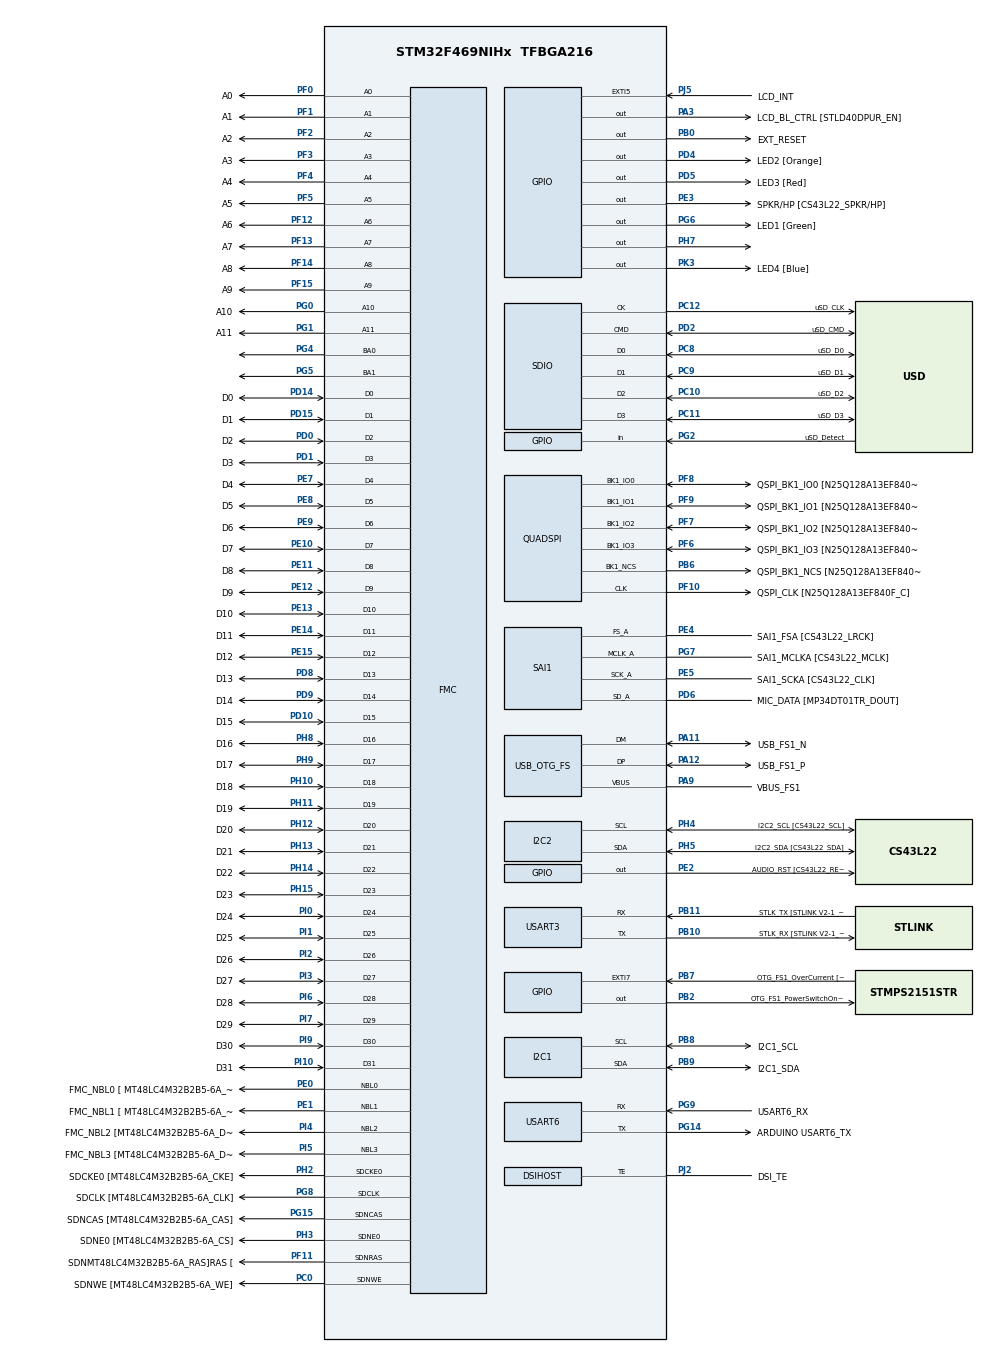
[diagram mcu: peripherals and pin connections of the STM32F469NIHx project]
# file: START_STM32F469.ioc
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DMA2D.ColorMode=DMA2D_OUTPUT_RGB565
DSIHOST.LPDcsLongWrite=DSI_LP_DLW_ENABLE
DSIHOST.LPDcsShortReadNoP=DSI_LP_DSR0P_ENABLE
DSIHOST.LPDcsShortWriteNoP=DSI_LP_DSW0P_ENABLE
DSIHOST.LPDcsShortWriteOneP=DSI_LP_DSW1P_ENABLE
DSIHOST.LPGenLongWrite=DSI_LP_GLW_ENABLE
DSIHOST.LPGenShortReadNoP=DSI_LP_GSR0P_ENABLE
DSIHOST.LPGenShortReadOneP=DSI_LP_GSR1P_ENABLE
DSIHOST.LPGenShortReadTwoP=DSI_LP_GSR2P_ENABLE
DSIHOST.LPGenShortWriteNoP=DSI_LP_GSW0P_ENABLE
DSIHOST.LPGenShortWriteOneP=DSI_LP_GSW1P_ENABLE
DSIHOST.LPGenShortWriteTwoP=DSI_LP_GSW2P_ENABLE
DSIHOST.LPMaxReadPacket=DSI_LP_MRDP_ENABLE
DSIHOST.NumberOfLanes=DSI_TWO_DATA_LANES
DSIHOST.StopWaitTime=10
DSIHOST.TEAcknowledgeRequest=DSI_TE_ACKNOWLEDGE_ENABLE
DSIHOST_CKN.GPIO_Label=DSI_CK_N
DSIHOST_CKN.Mode=DSIHost_Adapted_TE
DSIHOST_CKN.Signal=DSIHOST_CKN
DSIHOST_CKP.GPIO_Label=DSI_CK_P
DSIHOST_CKP.Mode=DSIHost_Adapted_TE
DSIHOST_CKP.Signal=DSIHOST_CKP
DSIHOST_D0N.GPIO_Label=DSI_D0_N
DSIHOST_D0N.Mode=DSIHost_Adapted_TE
DSIHOST_D0N.Signal=DSIHOST_D0N
DSIHOST_D0P.GPIO_Label=DSI_D0_P
DSIHOST_D0P.Mode=DSIHost_Adapted_TE
DSIHOST_D0P.Signal=DSIHOST_D0P
DSIHOST_D1N.GPIO_Label=DSI_D1_N
DSIHOST_D1N.Mode=DSIHost_Adapted_TE
DSIHOST_D1N.Signal=DSIHOST_D1N
DSIHOST_D1P.GPIO_Label=DSI_D1_P
DSIHOST_D1P.Mode=DSIHost_Adapted_TE
DSIHOST_D1P.Signal=DSIHOST_D1P
FATFS.BSP.number=1
FATFS0.BSP.STBoard=false
FATFS0.BSP.api=UnknownBspDriver
FATFS0.BSP.i2caddr=0
FATFS0.BSP.i2creg=0
FATFS0.BSP.instance=PG2
FATFS0.BSP.ip=GPIO
FATFS0.BSP.mode=Input
FATFS0.BSP.name=Detect_SDIO
FATFS0.BSP.solution=PG2
FMC.CASLatency1=FMC_SDRAM_CAS_LATENCY_1
FMC.ExitSelfRefreshDelay1=7
FMC.LoadToActiveDelay1=2
FMC.RCDDelay1=1
FMC.RPDelay1=1
FMC.RPDelay2=2
FMC.ReadBurst1=FMC_SDRAM_RBURST_ENABLE
FMC.ReadBurst2=FMC_SDRAM_RBURST_ENABLE
FMC.RowCycleDelay1=7
FMC.RowCycleDelay2=7
FMC.SDClockPeriod1=FMC_SDRAM_CLOCK_PERIOD_2
FMC.SDClockPeriod2=FMC_SDRAM_CLOCK_PERIOD_2
FMC.SelfRefreshTime1=4
FMC.WriteRecoveryTime1=3
LTDC.Alpha_L0=255
LTDC.BlendingFactor1_L0=LTDC_BLENDING_FACTOR1_PAxCA
LTDC.BlendingFactor2_L0=LTDC_BLENDING_FACTOR2_PAxCA
LTDC.FBStartAdress_L0=0xC0000000
LTDC.HBP=1
LTDC.HFP=1
LTDC.HSync=1
LTDC.ImageHeight_L0=480
LTDC.ImageWidth_L0=200
LTDC.Layers=0
LTDC.PixelFormat_L0=LTDC_PIXEL_FORMAT_RGB565
LTDC.VBP=1
LTDC.VFP=1
LTDC.VSync=1
LTDC.WindowX1_L0=200
LTDC.WindowY1_L0=480
Mcu.Family=STM32F4
Mcu.Name=STM32F469NIHx
Mcu.Package=TFBGA216
NVIC.DMA2D_IRQn=true\:0\:0\:false\:false\:true\:true\:true
NVIC.DSI_IRQn=true\:0\:0\:false\:false\:true\:true\:true
NVIC.LTDC_IRQn=true\:0\:0\:false\:false\:true\:true\:true
NVIC.OTG_FS_IRQn=true\:0\:0\:false\:false\:true\:true\:true
NVIC.PriorityGroup=NVIC_PRIORITYGROUP_4
NVIC.TIM6_DAC_IRQn=true\:0\:0\:false\:false\:true\:false\:true
NVIC.TimeBase=TIM6_DAC_IRQn
NVIC.TimeBaseIP=TIM6
PA0/WKUP.GPIO_Label=WAKEUP [B2]
PA0/WKUP.Mode=SYS_WakeUp0
PA0/WKUP.Signal=SYS_WKUP
PA10.GPIO_Label=USB_FS1_ID
PA10.GPIO_Mode=GPIO_MODE_AF_PP
PA10.GPIO_PuPd=GPIO_NOPULL
PA10.GPIO_Speed=GPIO_SPEED_FREQ_VERY_HIGH
PA10.Signal=USB_OTG_FS_ID
PA11.GPIO_Label=USB_FS1_N
PA11.GPIO_Mode=GPIO_MODE_AF_PP
PA11.GPIO_PuPd=GPIO_NOPULL
PA11.GPIO_Speed=GPIO_SPEED_FREQ_VERY_HIGH
PA11.Mode=Device_Only
PA11.Signal=USB_OTG_FS_DM
PA12.GPIO_Label=USB_FS1_P
PA12.GPIO_Mode=GPIO_MODE_AF_PP
PA12.GPIO_PuPd=GPIO_NOPULL
PA12.GPIO_Speed=GPIO_SPEED_FREQ_VERY_HIGH
PA12.Mode=Device_Only
PA12.Signal=USB_OTG_FS_DP
PA13.GPIO_Label=SWDIO
PA13.Mode=Serial_Wire
PA13.Signal=SYS_JTMS-SWDIO
PA14.GPIO_Label=SWCLK
PA14.Mode=Serial_Wire
PA14.Signal=SYS_JTCK-SWCLK
PA3.GPIO_Label=LCD_BL_CTRL [STLD40DPUR_EN]
PA3.GPIO_ModeDefaultOutputPP=GPIO_MODE_OUTPUT_PP
PA3.GPIO_PuPd=GPIO_NOPULL
PA3.GPIO_Speed=GPIO_SPEED_FREQ_LOW
PA3.Signal=GPIO_Output
PA9.GPIO_Label=VBUS_FS1
PA9.GPIO_Mode=GPIO_MODE_AF_PP
PA9.GPIO_PuPd=GPIO_NOPULL
PA9.GPIO_Speed=GPIO_SPEED_FREQ_VERY_HIGH
PA9.Mode=Activate_VBUS
PA9.Signal=USB_OTG_FS_VBUS
PB0.GPIO_Label=EXT_RESET
PB0.GPIO_ModeDefaultOutputPP=GPIO_MODE_OUTPUT_PP
PB0.GPIO_PuPd=GPIO_NOPULL
PB0.GPIO_Speed=GPIO_SPEED_FREQ_LOW
PB0.Signal=GPIO_Output
PB10.GPIO_Label=STLK_RX [STLINK V2-1_U2_RX]
PB10.GPIO_Mode=GPIO_MODE_AF_PP
PB10.GPIO_PuPd=GPIO_PULLUP
PB10.GPIO_Speed=GPIO_SPEED_FREQ_VERY_HIGH
PB10.Mode=Asynchronous
PB10.Signal=USART3_TX
PB11.GPIO_Label=STLK_TX [STLINK V2-1_U2_TX]
PB11.GPIO_Mode=GPIO_MODE_AF_PP
PB11.GPIO_PuPd=GPIO_PULLUP
PB11.GPIO_Speed=GPIO_SPEED_FREQ_VERY_HIGH
PB11.Mode=Asynchronous
PB11.Signal=USART3_RX
PB2/BOOT1.GPIO_Label=OTG_FS1_PowerSwitchOn [STMPS2151STR_En]
PB2/BOOT1.GPIO_ModeDefaultOutputPP=GPIO_MODE_OUTPUT_PP
PB2/BOOT1.GPIO_PuPd=GPIO_NOPULL
PB2/BOOT1.GPIO_Speed=GPIO_SPEED_FREQ_LOW
PB2/BOOT1.Signal=GPIO_Output
PB3.GPIO_Label=I2S3_CK
PB3.GPIO_Mode=GPIO_MODE_AF_PP
PB3.GPIO_PuPd=GPIO_NOPULL
PB3.GPIO_Speed=GPIO_SPEED_FREQ_LOW
PB3.Signal=I2S3_CK
PB6.GPIO_Label=QSPI_BK1_NCS [N25Q128A13EF840F_S]
PB6.GPIO_Mode=GPIO_MODE_AF_PP
PB6.GPIO_PuPd=GPIO_NOPULL
PB6.GPIO_Speed=GPIO_SPEED_FREQ_VERY_HIGH
PB6.Mode=Single Bank 1
PB6.Signal=QUADSPI_BK1_NCS
PB7.GPIO_Label=OTG_FS1_OverCurrent [STMPS2151STR_FAULT]
PB7.GPIO_ModeDefaultEXTI=GPIO_MODE_IT_RISING
PB7.GPIO_PuPd=GPIO_NOPULL
PB7.Signal=GPXTI7
PB8.GPIO_Label=I2C1_SCL
PB8.GPIO_Mode=GPIO_MODE_AF_OD
PB8.GPIO_PuPdOD=GPIO_PULLUP
PB8.GPIO_Speed=GPIO_SPEED_FREQ_VERY_HIGH
PB8.Mode=I2C
PB8.Signal=I2C1_SCL
PB9.GPIO_Label=I2C1_SDA
PB9.GPIO_Mode=GPIO_MODE_AF_OD
PB9.GPIO_PuPdOD=GPIO_PULLUP
PB9.GPIO_Speed=GPIO_SPEED_FREQ_VERY_HIGH
PB9.Mode=I2C
PB9.Signal=I2C1_SDA
PC0.GPIO_Label=SDNWE [MT48LC4M32B2B5-6A_WE]
PC0.GPIO_Mode=GPIO_MODE_AF_PP
PC0.GPIO_PuPd=GPIO_NOPULL
PC0.GPIO_Speed_High_Default=GPIO_SPEED_FREQ_VERY_HIGH
PC0.Signal=FMC_SDNWE
PC10.GPIO_Label=uSD_D2
PC10.GPIO_Mode=GPIO_MODE_AF_PP
PC10.GPIO_PuPd=GPIO_NOPULL
PC10.GPIO_Speed_High_Default=GPIO_SPEED_FREQ_VERY_HIGH
PC10.Mode=SD_4_bits_Wide_bus
PC10.Signal=SDIO_D2
PC11.GPIO_Label=uSD_D3
PC11.GPIO_Mode=GPIO_MODE_AF_PP
PC11.GPIO_PuPd=GPIO_NOPULL
PC11.GPIO_Speed_High_Default=GPIO_SPEED_FREQ_VERY_HIGH
PC11.Mode=SD_4_bits_Wide_bus
PC11.Signal=SDIO_D3
PC12.GPIO_Label=uSD_CLK
PC12.GPIO_Mode=GPIO_MODE_AF_PP
PC12.GPIO_PuPd=GPIO_NOPULL
PC12.GPIO_Speed_High_Default=GPIO_SPEED_FREQ_VERY_HIGH
PC12.Mode=SD_4_bits_Wide_bus
PC12.Signal=SDIO_CK
PC14/OSC32_IN.Mode=LSE-External-Oscillator
PC14/OSC32_IN.Signal=RCC_OSC32_IN
PC15/OSC32_OUT.Mode=LSE-External-Oscillator
PC15/OSC32_OUT.Signal=RCC_OSC32_OUT
PC8.GPIO_Label=uSD_D0
PC8.GPIO_Mode=GPIO_MODE_AF_PP
PC8.GPIO_PuPd=GPIO_NOPULL
PC8.GPIO_Speed_High_Default=GPIO_SPEED_FREQ_VERY_HIGH
PC8.Mode=SD_4_bits_Wide_bus
PC8.Signal=SDIO_D0
PC9.GPIO_Label=uSD_D1
PC9.GPIO_Mode=GPIO_MODE_AF_PP
PC9.GPIO_PuPd=GPIO_NOPULL
PC9.GPIO_Speed_High_Default=GPIO_SPEED_FREQ_VERY_HIGH
PC9.Mode=SD_4_bits_Wide_bus
PC9.Signal=SDIO_D1
PD0.GPIO_Label=D2
PD0.GPIO_Mode=GPIO_MODE_AF_PP
PD0.GPIO_PuPd=GPIO_NOPULL
PD0.GPIO_Speed_High_Default=GPIO_SPEED_FREQ_VERY_HIGH
PD0.Signal=FMC_D2_DA2
PD1.GPIO_Label=D3
PD1.GPIO_Mode=GPIO_MODE_AF_PP
PD1.GPIO_PuPd=GPIO_NOPULL
PD1.GPIO_Speed_High_Default=GPIO_SPEED_FREQ_VERY_HIGH
PD1.Signal=FMC_D3_DA3
PD10.GPIO_Label=D15
PD10.GPIO_Mode=GPIO_MODE_AF_PP
PD10.GPIO_PuPd=GPIO_NOPULL
PD10.GPIO_Speed_High_Default=GPIO_SPEED_FREQ_VERY_HIGH
PD10.Signal=FMC_D15_DA15
PD13.GPIO_Label=MIC_CK [MP34DT01TR_CLK]
PD13.GPIO_ModeDefaultPP=GPIO_MODE_AF_PP
PD13.GPIO_PuPd=GPIO_NOPULL
PD13.GPIO_Speed=GPIO_SPEED_FREQ_LOW
PD13.Signal=S_TIM4_CH2
PD14.GPIO_Label=D0
PD14.GPIO_Mode=GPIO_MODE_AF_PP
PD14.GPIO_PuPd=GPIO_NOPULL
PD14.GPIO_Speed_High_Default=GPIO_SPEED_FREQ_VERY_HIGH
PD14.Signal=FMC_D0_DA0
PD15.GPIO_Label=D1
PD15.GPIO_Mode=GPIO_MODE_AF_PP
PD15.GPIO_PuPd=GPIO_NOPULL
PD15.GPIO_Speed_High_Default=GPIO_SPEED_FREQ_VERY_HIGH
PD15.Signal=FMC_D1_DA1
PD2.GPIO_Label=uSD_CMD
PD2.GPIO_Mode=GPIO_MODE_AF_PP
PD2.GPIO_PuPd=GPIO_NOPULL
PD2.GPIO_Speed_High_Default=GPIO_SPEED_FREQ_VERY_HIGH
PD2.Mode=SD_4_bits_Wide_bus
PD2.Signal=SDIO_CMD
PD4.GPIO_Label=LED2 [Orange]
PD4.GPIO_ModeDefaultOutputPP=GPIO_MODE_OUTPUT_OD
PD4.GPIO_PuPd=GPIO_NOPULL
PD4.GPIO_Speed=GPIO_SPEED_FREQ_LOW
PD4.Signal=GPIO_Output
PD5.GPIO_Label=LED3 [Red]
PD5.GPIO_ModeDefaultOutputPP=GPIO_MODE_OUTPUT_OD
PD5.GPIO_PuPd=GPIO_NOPULL
PD5.GPIO_Speed=GPIO_SPEED_FREQ_LOW
PD5.Signal=GPIO_Output
PD6.GPIO_Label=MIC_DATA [MP34DT01TR_DOUT]
PD6.GPIO_Mode=GPIO_MODE_AF_PP
PD6.GPIO_PuPd=GPIO_NOPULL
PD6.GPIO_Speed=GPIO_SPEED_FREQ_LOW
PD6.Mode=SAI_A_MasterWithClock
PD6.Signal=SAI1_SD_A
PD8.GPIO_Label=D13
PD8.GPIO_Mode=GPIO_MODE_AF_PP
PD8.GPIO_PuPd=GPIO_NOPULL
PD8.GPIO_Speed_High_Default=GPIO_SPEED_FREQ_VERY_HIGH
PD8.Signal=FMC_D13_DA13
PD9.GPIO_Label=D14
PD9.GPIO_Mode=GPIO_MODE_AF_PP
PD9.GPIO_PuPd=GPIO_NOPULL
PD9.GPIO_Speed_High_Default=GPIO_SPEED_FREQ_VERY_HIGH
PD9.Signal=FMC_D14_DA14
PE0.GPIO_Label=FMC_NBL0 [ MT48LC4M32B2B5-6A_DQM0]
PE0.GPIO_Mode=GPIO_MODE_AF_PP
PE0.GPIO_PuPd=GPIO_NOPULL
PE0.GPIO_Speed_High_Default=GPIO_SPEED_FREQ_VERY_HIGH
PE0.Signal=FMC_NBL0
PE1.GPIO_Label=FMC_NBL1 [ MT48LC4M32B2B5-6A_DQM1]
PE1.GPIO_Mode=GPIO_MODE_AF_PP
PE1.GPIO_PuPd=GPIO_NOPULL
PE1.GPIO_Speed_High_Default=GPIO_SPEED_FREQ_VERY_HIGH
PE1.Signal=FMC_NBL1
PE10.GPIO_Label=D7
PE10.GPIO_Mode=GPIO_MODE_AF_PP
PE10.GPIO_PuPd=GPIO_NOPULL
PE10.GPIO_Speed_High_Default=GPIO_SPEED_FREQ_VERY_HIGH
PE10.Signal=FMC_D7_DA7
PE11.GPIO_Label=D8
PE11.GPIO_Mode=GPIO_MODE_AF_PP
PE11.GPIO_PuPd=GPIO_NOPULL
PE11.GPIO_Speed_High_Default=GPIO_SPEED_FREQ_VERY_HIGH
PE11.Signal=FMC_D8_DA8
PE12.GPIO_Label=D9
PE12.GPIO_Mode=GPIO_MODE_AF_PP
PE12.GPIO_PuPd=GPIO_NOPULL
PE12.GPIO_Speed_High_Default=GPIO_SPEED_FREQ_VERY_HIGH
PE12.Signal=FMC_D9_DA9
PE13.GPIO_Label=D10
PE13.GPIO_Mode=GPIO_MODE_AF_PP
PE13.GPIO_PuPd=GPIO_NOPULL
PE13.GPIO_Speed_High_Default=GPIO_SPEED_FREQ_VERY_HIGH
PE13.Signal=FMC_D10_DA10
PE14.GPIO_Label=D11
PE14.GPIO_Mode=GPIO_MODE_AF_PP
PE14.GPIO_PuPd=GPIO_NOPULL
PE14.GPIO_Speed_High_Default=GPIO_SPEED_FREQ_VERY_HIGH
PE14.Signal=FMC_D11_DA11
PE15.GPIO_Label=D12
PE15.GPIO_Mode=GPIO_MODE_AF_PP
PE15.GPIO_PuPd=GPIO_NOPULL
PE15.GPIO_Speed_High_Default=GPIO_SPEED_FREQ_VERY_HIGH
PE15.Signal=FMC_D12_DA12
PE2.GPIO_Label=AUDIO_RST [CS43L22_RESET]
PE2.GPIO_ModeDefaultOutputPP=GPIO_MODE_OUTPUT_PP
PE2.GPIO_PuPd=GPIO_NOPULL
PE2.GPIO_Speed=GPIO_SPEED_FREQ_LOW
PE2.Signal=GPIO_Output
PE3.GPIO_Label=SPKR/HP [CS43L22_SPKR/HP]
PE3.GPIO_ModeDefaultOutputPP=GPIO_MODE_OUTPUT_PP
PE3.GPIO_PuPd=GPIO_NOPULL
PE3.GPIO_Speed=GPIO_SPEED_FREQ_LOW
PE3.Signal=GPIO_Output
PE4.GPIO_Label=SAI1_FSA [CS43L22_LRCK]
PE4.GPIO_Mode=GPIO_MODE_AF_PP
PE4.GPIO_PuPd=GPIO_NOPULL
PE4.GPIO_Speed=GPIO_SPEED_FREQ_LOW
PE4.Mode=SAI_A_MasterWithClock
PE4.Signal=SAI1_FS_A
PE5.GPIO_Label=SAI1_SCKA [CS43L22_CLK]
PE5.GPIO_Mode=GPIO_MODE_AF_PP
PE5.GPIO_PuPd=GPIO_NOPULL
PE5.GPIO_Speed=GPIO_SPEED_FREQ_LOW
PE5.Mode=SAI_A_MasterWithClock
PE5.Signal=SAI1_SCK_A
PE7.GPIO_Label=D4
PE7.GPIO_Mode=GPIO_MODE_AF_PP
PE7.GPIO_PuPd=GPIO_NOPULL
PE7.GPIO_Speed_High_Default=GPIO_SPEED_FREQ_VERY_HIGH
PE7.Signal=FMC_D4_DA4
PE8.GPIO_Label=D5
PE8.GPIO_Mode=GPIO_MODE_AF_PP
PE8.GPIO_PuPd=GPIO_NOPULL
PE8.GPIO_Speed_High_Default=GPIO_SPEED_FREQ_VERY_HIGH
PE8.Signal=FMC_D5_DA5
PE9.GPIO_Label=D6
PE9.GPIO_Mode=GPIO_MODE_AF_PP
PE9.GPIO_PuPd=GPIO_NOPULL
PE9.GPIO_Speed_High_Default=GPIO_SPEED_FREQ_VERY_HIGH
PE9.Signal=FMC_D6_DA6
PF0.GPIO_Label=A0
PF0.GPIO_Mode=GPIO_MODE_AF_PP
PF0.GPIO_PuPd=GPIO_NOPULL
PF0.GPIO_Speed_High_Default=GPIO_SPEED_FREQ_VERY_HIGH
PF0.Signal=FMC_A0
PF1.GPIO_Label=A1
PF1.GPIO_Mode=GPIO_MODE_AF_PP
PF1.GPIO_PuPd=GPIO_NOPULL
PF1.GPIO_Speed_High_Default=GPIO_SPEED_FREQ_VERY_HIGH
PF1.Signal=FMC_A1
PF10.GPIO_Label=QSPI_CLK [N25Q128A13EF840F_C]
PF10.GPIO_Mode=GPIO_MODE_AF_PP
PF10.GPIO_PuPd=GPIO_NOPULL
PF10.GPIO_Speed=GPIO_SPEED_FREQ_VERY_HIGH
PF10.Mode=Single Bank 1
PF10.Signal=QUADSPI_CLK
PF11.GPIO_Label=SDNMT48LC4M32B2B5-6A_RAS]RAS [
PF11.GPIO_Mode=GPIO_MODE_AF_PP
PF11.GPIO_PuPd=GPIO_NOPULL
PF11.GPIO_Speed_High_Default=GPIO_SPEED_FREQ_VERY_HIGH
PF11.Signal=FMC_SDNRAS
PF12.GPIO_Label=A6
PF12.GPIO_Mode=GPIO_MODE_AF_PP
PF12.GPIO_PuPd=GPIO_NOPULL
PF12.GPIO_Speed_High_Default=GPIO_SPEED_FREQ_VERY_HIGH
PF12.Signal=FMC_A6
PF13.GPIO_Label=A7
PF13.GPIO_Mode=GPIO_MODE_AF_PP
PF13.GPIO_PuPd=GPIO_NOPULL
PF13.GPIO_Speed_High_Default=GPIO_SPEED_FREQ_VERY_HIGH
PF13.Signal=FMC_A7
PF14.GPIO_Label=A8
PF14.GPIO_Mode=GPIO_MODE_AF_PP
PF14.GPIO_PuPd=GPIO_NOPULL
PF14.GPIO_Speed_High_Default=GPIO_SPEED_FREQ_VERY_HIGH
PF14.Signal=FMC_A8
PF15.GPIO_Label=A9
PF15.GPIO_Mode=GPIO_MODE_AF_PP
PF15.GPIO_PuPd=GPIO_NOPULL
PF15.GPIO_Speed_High_Default=GPIO_SPEED_FREQ_VERY_HIGH
PF15.Signal=FMC_A9
PF2.GPIO_Label=A2
PF2.GPIO_Mode=GPIO_MODE_AF_PP
PF2.GPIO_PuPd=GPIO_NOPULL
PF2.GPIO_Speed_High_Default=GPIO_SPEED_FREQ_VERY_HIGH
PF2.Signal=FMC_A2
PF3.GPIO_Label=A3
PF3.GPIO_Mode=GPIO_MODE_AF_PP
PF3.GPIO_PuPd=GPIO_NOPULL
PF3.GPIO_Speed_High_Default=GPIO_SPEED_FREQ_VERY_HIGH
PF3.Signal=FMC_A3
PF4.GPIO_Label=A4
PF4.GPIO_Mode=GPIO_MODE_AF_PP
PF4.GPIO_PuPd=GPIO_NOPULL
PF4.GPIO_Speed_High_Default=GPIO_SPEED_FREQ_VERY_HIGH
PF4.Signal=FMC_A4
PF5.GPIO_Label=A5
PF5.GPIO_Mode=GPIO_MODE_AF_PP
PF5.GPIO_PuPd=GPIO_NOPULL
PF5.GPIO_Speed_High_Default=GPIO_SPEED_FREQ_VERY_HIGH
PF5.Signal=FMC_A5
PF6.GPIO_Label=QSPI_BK1_IO3 [N25Q128A13EF840F_DQ3]
PF6.GPIO_Mode=GPIO_MODE_AF_PP
PF6.GPIO_PuPd=GPIO_NOPULL
PF6.GPIO_Speed=GPIO_SPEED_FREQ_VERY_HIGH
PF6.Mode=Single Bank 1
PF6.Signal=QUADSPI_BK1_IO3
PF7.GPIO_Label=QSPI_BK1_IO2 [N25Q128A13EF840F_DQ2]
PF7.GPIO_Mode=GPIO_MODE_AF_PP
PF7.GPIO_PuPd=GPIO_NOPULL
PF7.GPIO_Speed=GPIO_SPEED_FREQ_VERY_HIGH
PF7.Mode=Single Bank 1
PF7.Signal=QUADSPI_BK1_IO2
PF8.GPIO_Label=QSPI_BK1_IO0 [N25Q128A13EF840F_DQ0]
PF8.GPIO_Mode=GPIO_MODE_AF_PP
PF8.GPIO_PuPd=GPIO_NOPULL
PF8.GPIO_Speed=GPIO_SPEED_FREQ_VERY_HIGH
PF8.Mode=Single Bank 1
PF8.Signal=QUADSPI_BK1_IO0
PF9.GPIO_Label=QSPI_BK1_IO1 [N25Q128A13EF840F_DQ1]
PF9.GPIO_Mode=GPIO_MODE_AF_PP
PF9.GPIO_PuPd=GPIO_NOPULL
PF9.GPIO_Speed=GPIO_SPEED_FREQ_VERY_HIGH
PF9.Mode=Single Bank 1
PF9.Signal=QUADSPI_BK1_IO1
PG0.GPIO_Label=A10
PG0.GPIO_Mode=GPIO_MODE_AF_PP
PG0.GPIO_PuPd=GPIO_NOPULL
PG0.GPIO_Speed_High_Default=GPIO_SPEED_FREQ_VERY_HIGH
PG0.Signal=FMC_A10
PG1.GPIO_Label=A11
PG1.GPIO_Mode=GPIO_MODE_AF_PP
PG1.GPIO_PuPd=GPIO_NOPULL
PG1.GPIO_Speed_High_Default=GPIO_SPEED_FREQ_VERY_HIGH
PG1.Signal=FMC_A11
PG14.GPIO_Label=ARDUINO USART6_TX
PG14.GPIO_Mode=GPIO_MODE_AF_PP
PG14.GPIO_PuPd=GPIO_NOPULL
PG14.GPIO_Speed=GPIO_SPEED_FREQ_VERY_HIGH
PG14.Mode=Asynchronous
PG14.Signal=USART6_TX
PG15.GPIO_Label=SDNCAS [MT48LC4M32B2B5-6A_CAS]
PG15.GPIO_Mode=GPIO_MODE_AF_PP
PG15.GPIO_PuPd=GPIO_NOPULL
PG15.GPIO_Speed_High_Default=GPIO_SPEED_FREQ_VERY_HIGH
PG15.Signal=FMC_SDNCAS
PG2.GPIO_Label=uSD_Detect
PG2.GPIO_Mode=GPIO_MODE_INPUT
PG2.GPIO_PuPd=GPIO_NOPULL
PG2.Signal=GPIO_Input
PG4.Signal=FMC_A14_BA0
PG5.Signal=FMC_A15_BA1
PG6.GPIO_Label=LED1 [Green]
PG6.GPIO_ModeDefaultOutputPP=GPIO_MODE_OUTPUT_OD
PG6.GPIO_PuPd=GPIO_NOPULL
PG6.GPIO_Speed=GPIO_SPEED_FREQ_LOW
PG6.Signal=GPIO_Output
PG7.GPIO_Label=SAI1_MCLKA [CS43L22_MCLK]
PG7.GPIO_Mode=GPIO_MODE_AF_PP
PG7.GPIO_PuPd=GPIO_NOPULL
PG7.GPIO_Speed=GPIO_SPEED_FREQ_LOW
PG7.Mode=SAI_A_MasterWithClock
PG7.Signal=SAI1_MCLK_A
PG8.GPIO_Label=SDCLK [MT48LC4M32B2B5-6A_CLK]
PG8.GPIO_Mode=GPIO_MODE_AF_PP
PG8.GPIO_PuPd=GPIO_NOPULL
PG8.GPIO_Speed_High_Default=GPIO_SPEED_FREQ_VERY_HIGH
PG8.Signal=FMC_SDCLK
PG9.GPIO_Label=USART6_RX
PG9.GPIO_Mode=GPIO_MODE_AF_PP
PG9.GPIO_PuPd=GPIO_NOPULL
PG9.GPIO_Speed=GPIO_SPEED_FREQ_VERY_HIGH
PG9.Mode=Asynchronous
PG9.Signal=USART6_RX
PH0/OSC_IN.Mode=HSE-External-Oscillator
PH0/OSC_IN.Signal=RCC_OSC_IN
PH1/OSC_OUT.Mode=HSE-External-Oscillator
PH1/OSC_OUT.Signal=RCC_OSC_OUT
PH10.GPIO_Label=D18
PH10.GPIO_Mode=GPIO_MODE_AF_PP
PH10.GPIO_PuPd=GPIO_NOPULL
PH10.GPIO_Speed_High_Default=GPIO_SPEED_FREQ_VERY_HIGH
PH10.Signal=FMC_D18
PH11.GPIO_Label=D19
PH11.GPIO_Mode=GPIO_MODE_AF_PP
PH11.GPIO_PuPd=GPIO_NOPULL
PH11.GPIO_Speed_High_Default=GPIO_SPEED_FREQ_VERY_HIGH
PH11.Signal=FMC_D19
PH12.GPIO_Label=D20
PH12.GPIO_Mode=GPIO_MODE_AF_PP
PH12.GPIO_PuPd=GPIO_NOPULL
PH12.GPIO_Speed_High_Default=GPIO_SPEED_FREQ_VERY_HIGH
PH12.Signal=FMC_D20
PH13.GPIO_Label=D21
PH13.GPIO_Mode=GPIO_MODE_AF_PP
PH13.GPIO_PuPd=GPIO_NOPULL
PH13.GPIO_Speed_High_Default=GPIO_SPEED_FREQ_VERY_HIGH
PH13.Signal=FMC_D21
PH14.GPIO_Label=D22
PH14.GPIO_Mode=GPIO_MODE_AF_PP
PH14.GPIO_PuPd=GPIO_NOPULL
PH14.GPIO_Speed_High_Default=GPIO_SPEED_FREQ_VERY_HIGH
PH14.Signal=FMC_D22
PH15.GPIO_Label=D23
PH15.GPIO_Mode=GPIO_MODE_AF_PP
PH15.GPIO_PuPd=GPIO_NOPULL
PH15.GPIO_Speed_High_Default=GPIO_SPEED_FREQ_VERY_HIGH
PH15.Signal=FMC_D23
PH2.GPIO_Label=SDCKE0 [MT48LC4M32B2B5-6A_CKE]
PH2.GPIO_Mode=GPIO_MODE_AF_PP
PH2.GPIO_PuPd=GPIO_NOPULL
PH2.GPIO_Speed_High_Default=GPIO_SPEED_FREQ_VERY_HIGH
PH2.Mode=SdramChipSelect1_1
PH2.Signal=FMC_SDCKE0
PH3.GPIO_Label=SDNE0 [MT48LC4M32B2B5-6A_CS]
PH3.GPIO_Mode=GPIO_MODE_AF_PP
PH3.GPIO_PuPd=GPIO_NOPULL
PH3.GPIO_Speed_High_Default=GPIO_SPEED_FREQ_VERY_HIGH
PH3.Mode=SdramChipSelect1_1
PH3.Signal=FMC_SDNE0
PH4.GPIO_Label=I2C2_SCL [CS43L22_SCL]
PH4.GPIO_Mode=GPIO_MODE_AF_OD
PH4.GPIO_PuPdOD=GPIO_PULLUP
PH4.GPIO_Speed=GPIO_SPEED_FREQ_VERY_HIGH
PH4.Mode=I2C
PH4.Signal=I2C2_SCL
PH5.GPIO_Label=I2C2_SDA [CS43L22_SDA]
PH5.GPIO_Mode=GPIO_MODE_AF_OD
PH5.GPIO_PuPdOD=GPIO_PULLUP
PH5.GPIO_Speed=GPIO_SPEED_FREQ_VERY_HIGH
PH5.Mode=I2C
PH5.Signal=I2C2_SDA
PH7.Signal=GPIO_Output
PH8.GPIO_Label=D16
PH8.GPIO_Mode=GPIO_MODE_AF_PP
PH8.GPIO_PuPd=GPIO_NOPULL
PH8.GPIO_Speed_High_Default=GPIO_SPEED_FREQ_VERY_HIGH
PH8.Signal=FMC_D16
PH9.GPIO_Label=D17
PH9.GPIO_Mode=GPIO_MODE_AF_PP
PH9.GPIO_PuPd=GPIO_NOPULL
PH9.GPIO_Speed_High_Default=GPIO_SPEED_FREQ_VERY_HIGH
PH9.Signal=FMC_D17
PI0.GPIO_Label=D24
PI0.GPIO_Mode=GPIO_MODE_AF_PP
PI0.GPIO_PuPd=GPIO_NOPULL
PI0.GPIO_Speed_High_Default=GPIO_SPEED_FREQ_VERY_HIGH
PI0.Signal=FMC_D24
PI1.GPIO_Label=D25
PI1.GPIO_Mode=GPIO_MODE_AF_PP
PI1.GPIO_PuPd=GPIO_NOPULL
PI1.GPIO_Speed_High_Default=GPIO_SPEED_FREQ_VERY_HIGH
PI1.Signal=FMC_D25
PI10.GPIO_Label=D31
PI10.GPIO_Mode=GPIO_MODE_AF_PP
PI10.GPIO_PuPd=GPIO_NOPULL
PI10.GPIO_Speed_High_Default=GPIO_SPEED_FREQ_VERY_HIGH
PI10.Signal=FMC_D31
PI2.GPIO_Label=D26
PI2.GPIO_Mode=GPIO_MODE_AF_PP
PI2.GPIO_PuPd=GPIO_NOPULL
PI2.GPIO_Speed_High_Default=GPIO_SPEED_FREQ_VERY_HIGH
PI2.Signal=FMC_D26
PI3.GPIO_Label=D27
PI3.GPIO_Mode=GPIO_MODE_AF_PP
PI3.GPIO_PuPd=GPIO_NOPULL
PI3.GPIO_Speed_High_Default=GPIO_SPEED_FREQ_VERY_HIGH
PI3.Signal=FMC_D27
PI4.GPIO_Label=FMC_NBL2 [MT48LC4M32B2B5-6A_DQM2]
PI4.GPIO_Mode=GPIO_MODE_AF_PP
PI4.GPIO_PuPd=GPIO_NOPULL
PI4.GPIO_Speed_High_Default=GPIO_SPEED_FREQ_VERY_HIGH
PI4.Signal=FMC_NBL2
PI5.GPIO_Label=FMC_NBL3 [MT48LC4M32B2B5-6A_DQM3]
PI5.GPIO_Mode=GPIO_MODE_AF_PP
PI5.GPIO_PuPd=GPIO_NOPULL
PI5.GPIO_Speed_High_Default=GPIO_SPEED_FREQ_VERY_HIGH
PI5.Signal=FMC_NBL3
PI6.GPIO_Label=D28
PI6.GPIO_Mode=GPIO_MODE_AF_PP
PI6.GPIO_PuPd=GPIO_NOPULL
PI6.GPIO_Speed_High_Default=GPIO_SPEED_FREQ_VERY_HIGH
PI6.Signal=FMC_D28
PI7.GPIO_Label=D29
PI7.GPIO_Mode=GPIO_MODE_AF_PP
PI7.GPIO_PuPd=GPIO_NOPULL
PI7.GPIO_Speed_High_Default=GPIO_SPEED_FREQ_VERY_HIGH
PI7.Signal=FMC_D29
PI9.GPIO_Label=D30
PI9.GPIO_Mode=GPIO_MODE_AF_PP
PI9.GPIO_PuPd=GPIO_NOPULL
PI9.GPIO_Speed_High_Default=GPIO_SPEED_FREQ_VERY_HIGH
PI9.Signal=FMC_D30
PJ2.GPIO_Label=DSI_TE
PJ2.GPIO_Mode=GPIO_MODE_AF_PP
PJ2.GPIO_PuPd=GPIO_NOPULL
PJ2.GPIO_Speed=GPIO_SPEED_FREQ_VERY_HIGH
PJ2.Mode=DSIHost_Adapted_TE
PJ2.Signal=DSIHOST_TE
PJ5.GPIO_Label=LCD_INT
PJ5.GPIO_ModeDefaultEXTI=GPIO_MODE_IT_RISING
PJ5.GPIO_PuPd=GPIO_NOPULL
PJ5.Signal=GPXTI5
PK3.GPIO_Label=LED4 [Blue]
PK3.GPIO_ModeDefaultOutputPP=GPIO_MODE_OUTPUT_OD
PK3.GPIO_PuPd=GPIO_NOPULL
PK3.GPIO_Speed=GPIO_SPEED_FREQ_LOW
PK3.Signal=GPIO_Output
ProjectManager.HeapSize=0x200
ProjectManager.StackSize=0x400
ProjectManager.TargetToolchain=STM32CubeIDE
QUADSPI.ClockPrescaler=2
RCC.AHBFreq_Value=168000000
RCC.APB1CLKDivider=RCC_HCLK_DIV4
RCC.APB1Freq_Value=42000000
RCC.APB1TimFreq_Value=84000000
RCC.APB2CLKDivider=RCC_HCLK_DIV2
RCC.APB2Freq_Value=84000000
RCC.APB2TimFreq_Value=168000000
RCC.CortexFreq_Value=168000000
RCC.HCLKFreq_Value=168000000
RCC.HSE_VALUE=8000000
RCC.PLLDSIIDF=DSI_PLL_IN_DIV2
RCC.PLLDSINDIV=125
RCC.PLLM=4
RCC.PLLN=168
RCC.PLLQ=6
RCC.PLLR=6
RCC.PLLSAIN=96
RCC.PLLSAIP=RCC_PLLSAIP_DIV4
RCC.PLLSAIQ=2
RCC.SYSCLKFreq_VALUE=168000000
RCC.SYSCLKSource=RCC_SYSCLKSOURCE_PLLCLK
RCC.USBCLockSelection=RCC_CLK48CLKSOURCE_PLLSAIP
RCC.USBFreq_Value=48000000
RCC.VCOOutputFreq_Value=336000000
SAI1.ErrorAudioFreq-SAI_A_MasterWithClock=-2.34 %
SAI1.Instance-SAI_A_MasterWithClock=SAI$Index_Block_A
SAI1.MClockEnable-SAI_A_MasterWithClock=SAI_MASTERCLOCK_ENABLE
SAI1.RealAudioFreq-SAI_A_MasterWithClock=187.5 KHz
SAI1.Synchro-SAI_A_MasterWithClock=SAI_ASYNCHRONOUS
SAI1.VirtualMode-SAI_A_MasterWithClock=VM_MASTER
SDIO.WideMode=SDIO_BUS_WIDE_4B
SH.FMC_A0.0=FMC_A0,12b-sda1
SH.FMC_A1.0=FMC_A1,12b-sda1
SH.FMC_A10.0=FMC_A10,12b-sda1
SH.FMC_A11.0=FMC_A11,12b-sda1
SH.FMC_A14_BA0.0=FMC_BA0,FourSdramBanks1
SH.FMC_A15_BA1.0=FMC_BA1,FourSdramBanks1
SH.FMC_A2.0=FMC_A2,12b-sda1
SH.FMC_A3.0=FMC_A3,12b-sda1
SH.FMC_A4.0=FMC_A4,12b-sda1
SH.FMC_A5.0=FMC_A5,12b-sda1
SH.FMC_A6.0=FMC_A6,12b-sda1
SH.FMC_A7.0=FMC_A7,12b-sda1
SH.FMC_A8.0=FMC_A8,12b-sda1
SH.FMC_A9.0=FMC_A9,12b-sda1
SH.FMC_D0_DA0.0=FMC_D0,sd-32b-d1
SH.FMC_D10_DA10.0=FMC_D10,sd-32b-d1
SH.FMC_D11_DA11.0=FMC_D11,sd-32b-d1
SH.FMC_D12_DA12.0=FMC_D12,sd-32b-d1
SH.FMC_D13_DA13.0=FMC_D13,sd-32b-d1
SH.FMC_D14_DA14.0=FMC_D14,sd-32b-d1
SH.FMC_D15_DA15.0=FMC_D15,sd-32b-d1
SH.FMC_D16.0=FMC_D16,sd-32b-d1
SH.FMC_D17.0=FMC_D17,sd-32b-d1
SH.FMC_D18.0=FMC_D18,sd-32b-d1
SH.FMC_D19.0=FMC_D19,sd-32b-d1
SH.FMC_D1_DA1.0=FMC_D1,sd-32b-d1
SH.FMC_D20.0=FMC_D20,sd-32b-d1
SH.FMC_D21.0=FMC_D21,sd-32b-d1
SH.FMC_D22.0=FMC_D22,sd-32b-d1
SH.FMC_D23.0=FMC_D23,sd-32b-d1
SH.FMC_D24.0=FMC_D24,sd-32b-d1
SH.FMC_D25.0=FMC_D25,sd-32b-d1
SH.FMC_D26.0=FMC_D26,sd-32b-d1
SH.FMC_D27.0=FMC_D27,sd-32b-d1
SH.FMC_D28.0=FMC_D28,sd-32b-d1
SH.FMC_D29.0=FMC_D29,sd-32b-d1
SH.FMC_D2_DA2.0=FMC_D2,sd-32b-d1
SH.FMC_D30.0=FMC_D30,sd-32b-d1
SH.FMC_D31.0=FMC_D31,sd-32b-d1
SH.FMC_D3_DA3.0=FMC_D3,sd-32b-d1
SH.FMC_D4_DA4.0=FMC_D4,sd-32b-d1
SH.FMC_D5_DA5.0=FMC_D5,sd-32b-d1
SH.FMC_D6_DA6.0=FMC_D6,sd-32b-d1
SH.FMC_D7_DA7.0=FMC_D7,sd-32b-d1
SH.FMC_D8_DA8.0=FMC_D8,sd-32b-d1
SH.FMC_D9_DA9.0=FMC_D9,sd-32b-d1
SH.FMC_NBL0.0=FMC_NBL0,Sd4ByteEnable1
SH.FMC_NBL1.0=FMC_NBL1,Sd4ByteEnable1
SH.FMC_NBL2.0=FMC_NBL2,Sd4ByteEnable1
SH.FMC_NBL3.0=FMC_NBL3,Sd4ByteEnable1
SH.FMC_SDCLK.0=FMC_SDCLK,12b-sda1
SH.FMC_SDNCAS.0=FMC_SDNCAS,12b-sda1
SH.FMC_SDNRAS.0=FMC_SDNRAS,12b-sda1
SH.FMC_SDNWE.0=FMC_SDNWE,12b-sda1
SH.S_TIM4_CH2.0=TIM4_CH2
USART3.VirtualMode=VM_ASYNC
USART6.VirtualMode=VM_ASYNC
USB_DEVICE.CLASS_NAME_FS=CDC
USB_DEVICE.PRODUCT_STRING_CDC_FS=klang
USB_DEVICE.VirtualMode-CDC_FS=Cdc
USB_DEVICE.VirtualModeFS=Cdc_FS
USB_OTG_FS.VirtualMode=Device_Only
VP_CRC_VS_CRC.Mode=CRC_Activate
VP_DMA2D_VS_DMA2D.Mode=DMA2D_Activate
VP_FATFS_VS_SDIO.Mode=SDIO
VP_LTDC_DSIMode.Mode=RGB888
VP_SYS_VS_tim6.Mode=TIM6
VP_TIM1_VS_ClockSourceINT.Mode=Internal
VP_USB_DEVICE_VS_USB_DEVICE_CDC_FS.Mode=CDC_FS
board=STM32F469I-DISCO

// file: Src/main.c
/* USER CODE BEGIN Header */
/**
  ******************************************************************************
  * @file           : main.c
  * @brief          : Main program body
  ******************************************************************************
  * @attention
  *
  * <h2><center>&copy; Copyright (c) 2019 STMicroelectronics.
  * All rights reserved.</center></h2>
  *
  * This software component is licensed by ST under Ultimate Liberty license
  * SLA0044, the "License"; You may not use this file except in compliance with
  * the License. You may obtain a copy of the License at:
  *                             www.st.com/SLA0044
  *
  ******************************************************************************
  */
/* USER CODE END Header */

#include "main.h"
#include "fatfs.h"
#include "usb_device.h"

CRC_HandleTypeDef hcrc;

DMA2D_HandleTypeDef hdma2d;

DSI_HandleTypeDef hdsi;

I2C_HandleTypeDef hi2c1;
I2C_HandleTypeDef hi2c2;

LTDC_HandleTypeDef hltdc;

QSPI_HandleTypeDef hqspi;

SAI_HandleTypeDef hsai_BlockA1;

SD_HandleTypeDef hsd;

TIM_HandleTypeDef htim1;

UART_HandleTypeDef huart3;
UART_HandleTypeDef huart6;

SDRAM_HandleTypeDef hsdram1;

void SystemClock_Config(void);
static void MX_GPIO_Init(void);
static void MX_CRC_Init(void);
static void MX_DMA2D_Init(void);
static void MX_DSIHOST_DSI_Init(void);
static void MX_FMC_Init(void);
static void MX_I2C1_Init(void);
static void MX_I2C2_Init(void);
static void MX_LTDC_Init(void);
static void MX_QUADSPI_Init(void);
static void MX_SAI1_Init(void);
static void MX_SDIO_SD_Init(void);
static void MX_TIM1_Init(void);
static void MX_USART3_UART_Init(void);
static void MX_USART6_UART_Init(void);

int main(void)
{
  /* USER CODE BEGIN 1 */
	//uint8_t  lcd_status = LCD_OK;
  /* USER CODE END 1 */

  /* MCU Configuration--------------------------------------------------------*/

  /* Reset of all peripherals, Initializes the Flash interface and the Systick. */
  HAL_Init();

  /* Configure the system clock */
  SystemClock_Config();

  /* Initialize all configured peripherals */
  MX_GPIO_Init();
  MX_CRC_Init();
  MX_DMA2D_Init();
  MX_DSIHOST_DSI_Init();
  MX_FMC_Init();
  MX_I2C1_Init();
  MX_I2C2_Init();
  MX_LTDC_Init();
  MX_QUADSPI_Init();
  MX_SAI1_Init();
  MX_SDIO_SD_Init();
  MX_TIM1_Init();
  MX_USART3_UART_Init();
  MX_USART6_UART_Init();
  MX_FATFS_Init();
  MX_USB_DEVICE_Init();
  /* USER CODE BEGIN 2 */
  BSP_LCD_InitEx(LCD_ORIENTATION_LANDSCAPE);
  BSP_LCD_Init() ;
  BSP_LCD_Clear(((uint32_t) 0xFFFFFFFF));
  /* USER CODE END 2 */

  /* Infinite loop */
  while (1)
  {

    /* USER CODE BEGIN 3 */

	  HAL_Delay(250);
	  HAL_GPIO_WritePin(LED1_GPIO_Port, LED1_Pin, GPIO_PIN_RESET);
	  HAL_Delay(250);
	  HAL_GPIO_WritePin(LED1_GPIO_Port, LED1_Pin, GPIO_PIN_SET);
  }
  /* USER CODE END 3 */
}

void SystemClock_Config(void)
{
  RCC_OscInitTypeDef RCC_OscInitStruct = {0};
  RCC_ClkInitTypeDef RCC_ClkInitStruct = {0};
  RCC_PeriphCLKInitTypeDef PeriphClkInitStruct = {0};

  /** Configure the main internal regulator output voltage
  */
  __HAL_RCC_PWR_CLK_ENABLE();
  __HAL_PWR_VOLTAGESCALING_CONFIG(PWR_REGULATOR_VOLTAGE_SCALE1);
  /** Initializes the CPU, AHB and APB busses clocks
  */
  RCC_OscInitStruct.OscillatorType = RCC_OSCILLATORTYPE_HSE;
  RCC_OscInitStruct.HSEState = RCC_HSE_ON;
  RCC_OscInitStruct.PLL.PLLState = RCC_PLL_ON;
  RCC_OscInitStruct.PLL.PLLSource = RCC_PLLSOURCE_HSE;
  RCC_OscInitStruct.PLL.PLLM = 4;
  RCC_OscInitStruct.PLL.PLLN = 180;
  RCC_OscInitStruct.PLL.PLLP = RCC_PLLP_DIV2;
  RCC_OscInitStruct.PLL.PLLQ = 6;
  RCC_OscInitStruct.PLL.PLLR = 6;
  if (HAL_RCC_OscConfig(&RCC_OscInitStruct) != HAL_OK)
  {
    Error_Handler();
  }
  /** Activate the Over-Drive mode
  */
  if (HAL_PWREx_EnableOverDrive() != HAL_OK)
  {
    Error_Handler();
  }
  /** Initializes the CPU, AHB and APB busses clocks
  */
  RCC_ClkInitStruct.ClockType = RCC_CLOCKTYPE_HCLK|RCC_CLOCKTYPE_SYSCLK
                              |RCC_CLOCKTYPE_PCLK1|RCC_CLOCKTYPE_PCLK2;
  RCC_ClkInitStruct.SYSCLKSource = RCC_SYSCLKSOURCE_PLLCLK;
  RCC_ClkInitStruct.AHBCLKDivider = RCC_SYSCLK_DIV1;
  RCC_ClkInitStruct.APB1CLKDivider = RCC_HCLK_DIV4;
  RCC_ClkInitStruct.APB2CLKDivider = RCC_HCLK_DIV2;

  if (HAL_RCC_ClockConfig(&RCC_ClkInitStruct, FLASH_LATENCY_5) != HAL_OK)
  {
    Error_Handler();
  }
  PeriphClkInitStruct.PeriphClockSelection = RCC_PERIPHCLK_SAI_PLLSAI|RCC_PERIPHCLK_SDIO
                              |RCC_PERIPHCLK_CLK48|RCC_PERIPHCLK_LTDC;
  PeriphClkInitStruct.PLLSAI.PLLSAIN = 144;
  PeriphClkInitStruct.PLLSAI.PLLSAIR = 2;
  PeriphClkInitStruct.PLLSAI.PLLSAIQ = 2;
  PeriphClkInitStruct.PLLSAI.PLLSAIP = RCC_PLLSAIP_DIV6;
  PeriphClkInitStruct.PLLSAIDivQ = 1;
  PeriphClkInitStruct.PLLSAIDivR = RCC_PLLSAIDIVR_4;
  PeriphClkInitStruct.Clk48ClockSelection = RCC_CLK48CLKSOURCE_PLLSAIP;
  PeriphClkInitStruct.SdioClockSelection = RCC_SDIOCLKSOURCE_CLK48;
  if (HAL_RCCEx_PeriphCLKConfig(&PeriphClkInitStruct) != HAL_OK)
  {
    Error_Handler();
  }
}

static void MX_CRC_Init(void)
{

  hcrc.Instance = CRC;
  if (HAL_CRC_Init(&hcrc) != HAL_OK)
  {
    Error_Handler();
  }

}

static void MX_DMA2D_Init(void)
{

  hdma2d.Instance = DMA2D;
  hdma2d.Init.Mode = DMA2D_M2M;
  hdma2d.Init.ColorMode = DMA2D_OUTPUT_ARGB8888;
  hdma2d.Init.OutputOffset = 0;
  hdma2d.LayerCfg[1].InputOffset = 0;
  hdma2d.LayerCfg[1].InputColorMode = DMA2D_INPUT_ARGB8888;
  hdma2d.LayerCfg[1].AlphaMode = DMA2D_NO_MODIF_ALPHA;
  hdma2d.LayerCfg[1].InputAlpha = 0;
  if (HAL_DMA2D_Init(&hdma2d) != HAL_OK)
  {
    Error_Handler();
  }
  if (HAL_DMA2D_ConfigLayer(&hdma2d, 1) != HAL_OK)
  {
    Error_Handler();
  }

}

static void MX_DSIHOST_DSI_Init(void)
{

  DSI_PLLInitTypeDef PLLInit = {0};
  DSI_HOST_TimeoutTypeDef HostTimeouts = {0};
  DSI_PHY_TimerTypeDef PhyTimings = {0};
  DSI_LPCmdTypeDef LPCmd = {0};
  DSI_CmdCfgTypeDef CmdCfg = {0};

  hdsi.Instance = DSI;
  hdsi.Init.AutomaticClockLaneControl = DSI_AUTO_CLK_LANE_CTRL_DISABLE;
  hdsi.Init.TXEscapeCkdiv = 4;
  hdsi.Init.NumberOfLanes = DSI_TWO_DATA_LANES;
  PLLInit.PLLNDIV = 125;
  PLLInit.PLLIDF = DSI_PLL_IN_DIV2;
  PLLInit.PLLODF = DSI_PLL_OUT_DIV1;
  if (HAL_DSI_Init(&hdsi, &PLLInit) != HAL_OK)
  {
    Error_Handler();
  }
  HostTimeouts.TimeoutCkdiv = 1;
  HostTimeouts.HighSpeedTransmissionTimeout = 0;
  HostTimeouts.LowPowerReceptionTimeout = 0;
  HostTimeouts.HighSpeedReadTimeout = 0;
  HostTimeouts.LowPowerReadTimeout = 0;
  HostTimeouts.HighSpeedWriteTimeout = 0;
  HostTimeouts.HighSpeedWritePrespMode = DSI_HS_PM_DISABLE;
  HostTimeouts.LowPowerWriteTimeout = 0;
  HostTimeouts.BTATimeout = 0;
  if (HAL_DSI_ConfigHostTimeouts(&hdsi, &HostTimeouts) != HAL_OK)
  {
    Error_Handler();
  }
  PhyTimings.ClockLaneHS2LPTime = 28;
  PhyTimings.ClockLaneLP2HSTime = 33;
  PhyTimings.DataLaneHS2LPTime = 15;
  PhyTimings.DataLaneLP2HSTime = 25;
  PhyTimings.DataLaneMaxReadTime = 0;
  PhyTimings.StopWaitTime = 10;
  if (HAL_DSI_ConfigPhyTimer(&hdsi, &PhyTimings) != HAL_OK)
  {
    Error_Handler();
  }
  if (HAL_DSI_ConfigFlowControl(&hdsi, DSI_FLOW_CONTROL_BTA) != HAL_OK)
  {
    Error_Handler();
  }
  if (HAL_DSI_SetLowPowerRXFilter(&hdsi, 10000) != HAL_OK)
  {
    Error_Handler();
  }
  if (HAL_DSI_ConfigErrorMonitor(&hdsi, HAL_DSI_ERROR_NONE) != HAL_OK)
  {
    Error_Handler();
  }
  LPCmd.LPGenShortWriteNoP = DSI_LP_GSW0P_ENABLE;
  LPCmd.LPGenShortWriteOneP = DSI_LP_GSW1P_ENABLE;
  LPCmd.LPGenShortWriteTwoP = DSI_LP_GSW2P_ENABLE;
  LPCmd.LPGenShortReadNoP = DSI_LP_GSR0P_ENABLE;
  LPCmd.LPGenShortReadOneP = DSI_LP_GSR1P_ENABLE;
  LPCmd.LPGenShortReadTwoP = DSI_LP_GSR2P_ENABLE;
  LPCmd.LPGenLongWrite = DSI_LP_GLW_ENABLE;
  LPCmd.LPDcsShortWriteNoP = DSI_LP_DSW0P_ENABLE;
  LPCmd.LPDcsShortWriteOneP = DSI_LP_DSW1P_ENABLE;
  LPCmd.LPDcsShortReadNoP = DSI_LP_DSR0P_ENABLE;
  LPCmd.LPDcsLongWrite = DSI_LP_DLW_ENABLE;
  LPCmd.LPMaxReadPacket = DSI_LP_MRDP_ENABLE;
  LPCmd.AcknowledgeRequest = DSI_ACKNOWLEDGE_DISABLE;
  if (HAL_DSI_ConfigCommand(&hdsi, &LPCmd) != HAL_OK)
  {
    Error_Handler();
  }
  CmdCfg.VirtualChannelID = 0;
  CmdCfg.ColorCoding = DSI_RGB888;
  CmdCfg.CommandSize = 200;
  CmdCfg.TearingEffectSource = DSI_TE_EXTERNAL;
  CmdCfg.TearingEffectPolarity = DSI_TE_RISING_EDGE;
  CmdCfg.HSPolarity = DSI_HSYNC_ACTIVE_LOW;
  CmdCfg.VSPolarity = DSI_VSYNC_ACTIVE_LOW;
  CmdCfg.DEPolarity = DSI_DATA_ENABLE_ACTIVE_HIGH;
  CmdCfg.VSyncPol = DSI_VSYNC_FALLING;
  CmdCfg.AutomaticRefresh = DSI_AR_ENABLE;
  CmdCfg.TEAcknowledgeRequest = DSI_TE_ACKNOWLEDGE_ENABLE;
  if (HAL_DSI_ConfigAdaptedCommandMode(&hdsi, &CmdCfg) != HAL_OK)
  {
    Error_Handler();
  }
  if (HAL_DSI_SetGenericVCID(&hdsi, 0) != HAL_OK)
  {
    Error_Handler();
  }

}

static void MX_I2C1_Init(void)
{

  hi2c1.Instance = I2C1;
  hi2c1.Init.ClockSpeed = 100000;
  hi2c1.Init.DutyCycle = I2C_DUTYCYCLE_2;
  hi2c1.Init.OwnAddress1 = 0;
  hi2c1.Init.AddressingMode = I2C_ADDRESSINGMODE_7BIT;
  hi2c1.Init.DualAddressMode = I2C_DUALADDRESS_DISABLE;
  hi2c1.Init.OwnAddress2 = 0;
  hi2c1.Init.GeneralCallMode = I2C_GENERALCALL_DISABLE;
  hi2c1.Init.NoStretchMode = I2C_NOSTRETCH_DISABLE;
  if (HAL_I2C_Init(&hi2c1) != HAL_OK)
  {
    Error_Handler();
  }

}

static void MX_I2C2_Init(void)
{

  hi2c2.Instance = I2C2;
  hi2c2.Init.ClockSpeed = 100000;
  hi2c2.Init.DutyCycle = I2C_DUTYCYCLE_2;
  hi2c2.Init.OwnAddress1 = 0;
  hi2c2.Init.AddressingMode = I2C_ADDRESSINGMODE_7BIT;
  hi2c2.Init.DualAddressMode = I2C_DUALADDRESS_DISABLE;
  hi2c2.Init.OwnAddress2 = 0;
  hi2c2.Init.GeneralCallMode = I2C_GENERALCALL_DISABLE;
  hi2c2.Init.NoStretchMode = I2C_NOSTRETCH_DISABLE;
  if (HAL_I2C_Init(&hi2c2) != HAL_OK)
  {
    Error_Handler();
  }

}

static void MX_LTDC_Init(void)
{

  LTDC_LayerCfgTypeDef pLayerCfg = {0};

  hltdc.Instance = LTDC;
  hltdc.Init.HSPolarity = LTDC_HSPOLARITY_AL;
  hltdc.Init.VSPolarity = LTDC_VSPOLARITY_AL;
  hltdc.Init.DEPolarity = LTDC_DEPOLARITY_AL;
  hltdc.Init.PCPolarity = LTDC_PCPOLARITY_IPC;
  hltdc.Init.HorizontalSync = 0;
  hltdc.Init.VerticalSync = 0;
  hltdc.Init.AccumulatedHBP = 1;
  hltdc.Init.AccumulatedVBP = 1;
  hltdc.Init.AccumulatedActiveW = 201;
  hltdc.Init.AccumulatedActiveH = 481;
  hltdc.Init.TotalWidth = 202;
  hltdc.Init.TotalHeigh = 482;
  hltdc.Init.Backcolor.Blue = 0;
  hltdc.Init.Backcolor.Green = 0;
  hltdc.Init.Backcolor.Red = 0;
  if (HAL_LTDC_Init(&hltdc) != HAL_OK)
  {
    Error_Handler();
  }
  pLayerCfg.WindowX0 = 0;
  pLayerCfg.WindowX1 = 200;
  pLayerCfg.WindowY0 = 0;
  pLayerCfg.WindowY1 = 480;
  pLayerCfg.PixelFormat = LTDC_PIXEL_FORMAT_RGB565;
  pLayerCfg.Alpha = 255;
  pLayerCfg.Alpha0 = 0;
  pLayerCfg.BlendingFactor1 = LTDC_BLENDING_FACTOR1_PAxCA;
  pLayerCfg.BlendingFactor2 = LTDC_BLENDING_FACTOR2_PAxCA;
  pLayerCfg.FBStartAdress = 0xC0000000;
  pLayerCfg.ImageWidth = 200;
  pLayerCfg.ImageHeight = 480;
  pLayerCfg.Backcolor.Blue = 0;
  pLayerCfg.Backcolor.Green = 0;
  pLayerCfg.Backcolor.Red = 0;
  if (HAL_LTDC_ConfigLayer(&hltdc, &pLayerCfg, 0) != HAL_OK)
  {
    Error_Handler();
  }

}

static void MX_QUADSPI_Init(void)
{

  /* QUADSPI parameter configuration*/
  hqspi.Instance = QUADSPI;
  hqspi.Init.ClockPrescaler = 255;
  hqspi.Init.FifoThreshold = 1;
  hqspi.Init.SampleShifting = QSPI_SAMPLE_SHIFTING_NONE;
  hqspi.Init.FlashSize = 1;
  hqspi.Init.ChipSelectHighTime = QSPI_CS_HIGH_TIME_1_CYCLE;
  hqspi.Init.ClockMode = QSPI_CLOCK_MODE_0;
  hqspi.Init.FlashID = QSPI_FLASH_ID_1;
  hqspi.Init.DualFlash = QSPI_DUALFLASH_DISABLE;
  if (HAL_QSPI_Init(&hqspi) != HAL_OK)
  {
    Error_Handler();
  }

}

static void MX_SAI1_Init(void)
{

  hsai_BlockA1.Instance = SAI1_Block_A;
  hsai_BlockA1.Init.Protocol = SAI_FREE_PROTOCOL;
  hsai_BlockA1.Init.AudioMode = SAI_MODEMASTER_TX;
  hsai_BlockA1.Init.DataSize = SAI_DATASIZE_8;
  hsai_BlockA1.Init.FirstBit = SAI_FIRSTBIT_MSB;
  hsai_BlockA1.Init.ClockStrobing = SAI_CLOCKSTROBING_FALLINGEDGE;
  hsai_BlockA1.Init.Synchro = SAI_ASYNCHRONOUS;
  hsai_BlockA1.Init.OutputDrive = SAI_OUTPUTDRIVE_DISABLE;
  hsai_BlockA1.Init.NoDivider = SAI_MASTERDIVIDER_ENABLE;
  hsai_BlockA1.Init.FIFOThreshold = SAI_FIFOTHRESHOLD_EMPTY;
  hsai_BlockA1.Init.ClockSource = SAI_CLKSOURCE_PLLSAI;
  hsai_BlockA1.Init.AudioFrequency = SAI_AUDIO_FREQUENCY_192K;
  hsai_BlockA1.Init.SynchroExt = SAI_SYNCEXT_DISABLE;
  hsai_BlockA1.Init.MonoStereoMode = SAI_STEREOMODE;
  hsai_BlockA1.Init.CompandingMode = SAI_NOCOMPANDING;
  hsai_BlockA1.Init.TriState = SAI_OUTPUT_NOTRELEASED;
  hsai_BlockA1.FrameInit.FrameLength = 8;
  hsai_BlockA1.FrameInit.ActiveFrameLength = 1;
  hsai_BlockA1.FrameInit.FSDefinition = SAI_FS_STARTFRAME;
  hsai_BlockA1.FrameInit.FSPolarity = SAI_FS_ACTIVE_LOW;
  hsai_BlockA1.FrameInit.FSOffset = SAI_FS_FIRSTBIT;
  hsai_BlockA1.SlotInit.FirstBitOffset = 0;
  hsai_BlockA1.SlotInit.SlotSize = SAI_SLOTSIZE_DATASIZE;
  hsai_BlockA1.SlotInit.SlotNumber = 1;
  hsai_BlockA1.SlotInit.SlotActive = 0x00000000;
  if (HAL_SAI_Init(&hsai_BlockA1) != HAL_OK)
  {
    Error_Handler();
  }

}

static void MX_SDIO_SD_Init(void)
{

  hsd.Instance = SDIO;
  hsd.Init.ClockEdge = SDIO_CLOCK_EDGE_RISING;
  hsd.Init.ClockBypass = SDIO_CLOCK_BYPASS_DISABLE;
  hsd.Init.ClockPowerSave = SDIO_CLOCK_POWER_SAVE_DISABLE;
  hsd.Init.BusWide = SDIO_BUS_WIDE_1B;
  hsd.Init.HardwareFlowControl = SDIO_HARDWARE_FLOW_CONTROL_DISABLE;
  hsd.Init.ClockDiv = 0;

}

static void MX_TIM1_Init(void)
{

  TIM_ClockConfigTypeDef sClockSourceConfig = {0};
  TIM_MasterConfigTypeDef sMasterConfig = {0};

  htim1.Instance = TIM1;
  htim1.Init.Prescaler = 0;
  htim1.Init.CounterMode = TIM_COUNTERMODE_UP;
  htim1.Init.Period = 0;
  htim1.Init.ClockDivision = TIM_CLOCKDIVISION_DIV1;
  htim1.Init.RepetitionCounter = 0;
  htim1.Init.AutoReloadPreload = TIM_AUTORELOAD_PRELOAD_DISABLE;
  if (HAL_TIM_Base_Init(&htim1) != HAL_OK)
  {
    Error_Handler();
  }
  sClockSourceConfig.ClockSource = TIM_CLOCKSOURCE_INTERNAL;
  if (HAL_TIM_ConfigClockSource(&htim1, &sClockSourceConfig) != HAL_OK)
  {
    Error_Handler();
  }
  sMasterConfig.MasterOutputTrigger = TIM_TRGO_RESET;
  sMasterConfig.MasterSlaveMode = TIM_MASTERSLAVEMODE_DISABLE;
  if (HAL_TIMEx_MasterConfigSynchronization(&htim1, &sMasterConfig) != HAL_OK)
  {
    Error_Handler();
  }

}

static void MX_USART3_UART_Init(void)
{

  huart3.Instance = USART3;
  huart3.Init.BaudRate = 115200;
  huart3.Init.WordLength = UART_WORDLENGTH_8B;
  huart3.Init.StopBits = UART_STOPBITS_1;
  huart3.Init.Parity = UART_PARITY_NONE;
  huart3.Init.Mode = UART_MODE_TX_RX;
  huart3.Init.HwFlowCtl = UART_HWCONTROL_NONE;
  huart3.Init.OverSampling = UART_OVERSAMPLING_16;
  if (HAL_UART_Init(&huart3) != HAL_OK)
  {
    Error_Handler();
  }

}

static void MX_USART6_UART_Init(void)
{

  huart6.Instance = USART6;
  huart6.Init.BaudRate = 115200;
  huart6.Init.WordLength = UART_WORDLENGTH_8B;
  huart6.Init.StopBits = UART_STOPBITS_1;
  huart6.Init.Parity = UART_PARITY_NONE;
  huart6.Init.Mode = UART_MODE_TX_RX;
  huart6.Init.HwFlowCtl = UART_HWCONTROL_NONE;
  huart6.Init.OverSampling = UART_OVERSAMPLING_16;
  if (HAL_UART_Init(&huart6) != HAL_OK)
  {
    Error_Handler();
  }

}

/* FMC initialization function */
static void MX_FMC_Init(void)
{

  FMC_SDRAM_TimingTypeDef SdramTiming = {0};

  /** Perform the SDRAM1 memory initialization sequence
  */
  hsdram1.Instance = FMC_SDRAM_DEVICE;
  /* hsdram1.Init */
  hsdram1.Init.SDBank = FMC_SDRAM_BANK1;
  hsdram1.Init.ColumnBitsNumber = FMC_SDRAM_COLUMN_BITS_NUM_8;
  hsdram1.Init.RowBitsNumber = FMC_SDRAM_ROW_BITS_NUM_12;
  hsdram1.Init.MemoryDataWidth = FMC_SDRAM_MEM_BUS_WIDTH_32;
  hsdram1.Init.InternalBankNumber = FMC_SDRAM_INTERN_BANKS_NUM_4;
  hsdram1.Init.CASLatency = FMC_SDRAM_CAS_LATENCY_3;
  hsdram1.Init.WriteProtection = FMC_SDRAM_WRITE_PROTECTION_DISABLE;
  hsdram1.Init.SDClockPeriod = FMC_SDRAM_CLOCK_PERIOD_2;
  hsdram1.Init.ReadBurst = FMC_SDRAM_RBURST_ENABLE;
  hsdram1.Init.ReadPipeDelay = FMC_SDRAM_RPIPE_DELAY_0;
  /* SdramTiming */
  SdramTiming.LoadToActiveDelay = 2;
  SdramTiming.ExitSelfRefreshDelay = 7;
  SdramTiming.SelfRefreshTime = 4;
  SdramTiming.RowCycleDelay = 7;
  SdramTiming.WriteRecoveryTime = 3;
  SdramTiming.RPDelay = 2;
  SdramTiming.RCDDelay = 2;

  if (HAL_SDRAM_Init(&hsdram1, &SdramTiming) != HAL_OK)
  {
    Error_Handler( );
  }

}

static void MX_GPIO_Init(void)
{
  GPIO_InitTypeDef GPIO_InitStruct = {0};

  /* GPIO Ports Clock Enable */
  __HAL_RCC_GPIOE_CLK_ENABLE();
  __HAL_RCC_GPIOG_CLK_ENABLE();
  __HAL_RCC_GPIOB_CLK_ENABLE();
  __HAL_RCC_GPIOC_CLK_ENABLE();
  __HAL_RCC_GPIOA_CLK_ENABLE();
  __HAL_RCC_GPIOD_CLK_ENABLE();
  __HAL_RCC_GPIOI_CLK_ENABLE();
  __HAL_RCC_GPIOF_CLK_ENABLE();
  __HAL_RCC_GPIOK_CLK_ENABLE();
  __HAL_RCC_GPIOH_CLK_ENABLE();
  __HAL_RCC_GPIOJ_CLK_ENABLE();

  /*Configure GPIO pin Output Level */
  HAL_GPIO_WritePin(GPIOE, SPKR_HP_Pin|AUDIO_RST_Pin, GPIO_PIN_RESET);

  /*Configure GPIO pin Output Level */
  HAL_GPIO_WritePin(GPIOD, LED3_Pin|LED2_Pin, GPIO_PIN_RESET);

  /*Configure GPIO pin Output Level */
  HAL_GPIO_WritePin(LED4_GPIO_Port, LED4_Pin, GPIO_PIN_RESET);

  /*Configure GPIO pin Output Level */
  HAL_GPIO_WritePin(LED1_GPIO_Port, LED1_Pin, GPIO_PIN_RESET);

  /*Configure GPIO pin Output Level */
  HAL_GPIO_WritePin(GPIOB, OTG_FS1_PowerSwitchOn_Pin|EXT_RESET_Pin, GPIO_PIN_RESET);

  /*Configure GPIO pin Output Level */
  HAL_GPIO_WritePin(GPIOH, GPIO_PIN_7, GPIO_PIN_RESET);

  /*Configure GPIO pin Output Level */
  HAL_GPIO_WritePin(LCD_BL_CTRL_GPIO_Port, LCD_BL_CTRL_Pin, GPIO_PIN_RESET);

  /*Configure GPIO pins : SPKR_HP_Pin AUDIO_RST_Pin */
  GPIO_InitStruct.Pin = SPKR_HP_Pin|AUDIO_RST_Pin;
  GPIO_InitStruct.Mode = GPIO_MODE_OUTPUT_PP;
  GPIO_InitStruct.Pull = GPIO_NOPULL;
  GPIO_InitStruct.Speed = GPIO_SPEED_FREQ_LOW;
  HAL_GPIO_Init(GPIOE, &GPIO_InitStruct);

  /*Configure GPIO pin : I2S3_CK_Pin */
  GPIO_InitStruct.Pin = I2S3_CK_Pin;
  GPIO_InitStruct.Mode = GPIO_MODE_AF_PP;
  GPIO_InitStruct.Pull = GPIO_NOPULL;
  GPIO_InitStruct.Speed = GPIO_SPEED_FREQ_LOW;
  GPIO_InitStruct.Alternate = GPIO_AF6_SPI3;
  HAL_GPIO_Init(I2S3_CK_GPIO_Port, &GPIO_InitStruct);

  /*Configure GPIO pin : OTG_FS1_OverCurrent_Pin */
  GPIO_InitStruct.Pin = OTG_FS1_OverCurrent_Pin;
  GPIO_InitStruct.Mode = GPIO_MODE_IT_RISING;
  GPIO_InitStruct.Pull = GPIO_NOPULL;
  HAL_GPIO_Init(OTG_FS1_OverCurrent_GPIO_Port, &GPIO_InitStruct);

  /*Configure GPIO pins : LED3_Pin LED2_Pin */
  GPIO_InitStruct.Pin = LED3_Pin|LED2_Pin;
  GPIO_InitStruct.Mode = GPIO_MODE_OUTPUT_OD;
  GPIO_InitStruct.Pull = GPIO_NOPULL;
  GPIO_InitStruct.Speed = GPIO_SPEED_FREQ_LOW;
  HAL_GPIO_Init(GPIOD, &GPIO_InitStruct);

  /*Configure GPIO pin : LED4_Pin */
  GPIO_InitStruct.Pin = LED4_Pin;
  GPIO_InitStruct.Mode = GPIO_MODE_OUTPUT_OD;
  GPIO_InitStruct.Pull = GPIO_NOPULL;
  GPIO_InitStruct.Speed = GPIO_SPEED_FREQ_LOW;
  HAL_GPIO_Init(LED4_GPIO_Port, &GPIO_InitStruct);

  /*Configure GPIO pin : LED1_Pin */
  GPIO_InitStruct.Pin = LED1_Pin;
  GPIO_InitStruct.Mode = GPIO_MODE_OUTPUT_OD;
  GPIO_InitStruct.Pull = GPIO_NOPULL;
  GPIO_InitStruct.Speed = GPIO_SPEED_FREQ_LOW;
  HAL_GPIO_Init(LED1_GPIO_Port, &GPIO_InitStruct);

  /*Configure GPIO pins : OTG_FS1_PowerSwitchOn_Pin EXT_RESET_Pin */
  GPIO_InitStruct.Pin = OTG_FS1_PowerSwitchOn_Pin|EXT_RESET_Pin;
  GPIO_InitStruct.Mode = GPIO_MODE_OUTPUT_PP;
  GPIO_InitStruct.Pull = GPIO_NOPULL;
  GPIO_InitStruct.Speed = GPIO_SPEED_FREQ_LOW;
  HAL_GPIO_Init(GPIOB, &GPIO_InitStruct);

  /*Configure GPIO pin : MIC_CK_Pin */
  GPIO_InitStruct.Pin = MIC_CK_Pin;
  GPIO_InitStruct.Mode = GPIO_MODE_AF_PP;
  GPIO_InitStruct.Pull = GPIO_NOPULL;
  GPIO_InitStruct.Speed = GPIO_SPEED_FREQ_LOW;
  GPIO_InitStruct.Alternate = GPIO_AF2_TIM4;
  HAL_GPIO_Init(MIC_CK_GPIO_Port, &GPIO_InitStruct);

  /*Configure GPIO pin : uSD_Detect_Pin */
  GPIO_InitStruct.Pin = uSD_Detect_Pin;
  GPIO_InitStruct.Mode = GPIO_MODE_INPUT;
  GPIO_InitStruct.Pull = GPIO_NOPULL;
  HAL_GPIO_Init(uSD_Detect_GPIO_Port, &GPIO_InitStruct);

  /*Configure GPIO pin : LCD_INT_Pin */
  GPIO_InitStruct.Pin = LCD_INT_Pin;
  GPIO_InitStruct.Mode = GPIO_MODE_IT_RISING;
  GPIO_InitStruct.Pull = GPIO_NOPULL;
  HAL_GPIO_Init(LCD_INT_GPIO_Port, &GPIO_InitStruct);

  /*Configure GPIO pin : PH7 */
  GPIO_InitStruct.Pin = GPIO_PIN_7;
  GPIO_InitStruct.Mode = GPIO_MODE_OUTPUT_PP;
  GPIO_InitStruct.Pull = GPIO_NOPULL;
  GPIO_InitStruct.Speed = GPIO_SPEED_FREQ_LOW;
  HAL_GPIO_Init(GPIOH, &GPIO_InitStruct);

  /*Configure GPIO pin : LCD_BL_CTRL_Pin */
  GPIO_InitStruct.Pin = LCD_BL_CTRL_Pin;
  GPIO_InitStruct.Mode = GPIO_MODE_OUTPUT_PP;
  GPIO_InitStruct.Pull = GPIO_NOPULL;
  GPIO_InitStruct.Speed = GPIO_SPEED_FREQ_LOW;
  HAL_GPIO_Init(LCD_BL_CTRL_GPIO_Port, &GPIO_InitStruct);

}

void HAL_TIM_PeriodElapsedCallback(TIM_HandleTypeDef *htim)
{
  if (htim->Instance == TIM6) {
    HAL_IncTick();
  }
}

void Error_Handler(void)
{
}

/************************ (C) COPYRIGHT STMicroelectronics *****END OF FILE****/
